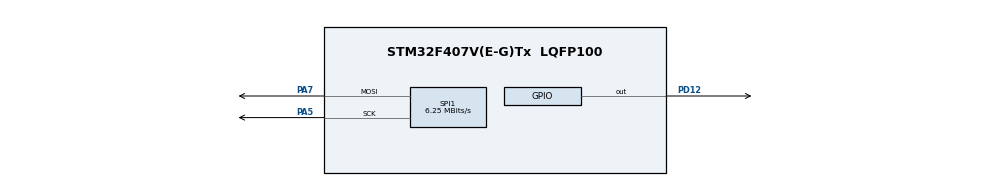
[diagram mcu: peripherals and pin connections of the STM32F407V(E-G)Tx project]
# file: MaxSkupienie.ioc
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Mcu.Family=STM32F4
Mcu.Name=STM32F407V(E-G)Tx
Mcu.Package=LQFP100
NVIC.PriorityGroup=NVIC_PRIORITYGROUP_4
PA13.Mode=Serial_Wire
PA13.Signal=SYS_JTMS-SWDIO
PA14.Mode=Serial_Wire
PA14.Signal=SYS_JTCK-SWCLK
PA5.Mode=TX_Only_Simplex_Unidirect_Master
PA5.Signal=SPI1_SCK
PA7.Mode=TX_Only_Simplex_Unidirect_Master
PA7.Signal=SPI1_MOSI
PC14-OSC32_IN.Mode=LSE-External-Oscillator
PC14-OSC32_IN.Signal=RCC_OSC32_IN
PC15-OSC32_OUT.Mode=LSE-External-Oscillator
PC15-OSC32_OUT.Signal=RCC_OSC32_OUT
PD12.Signal=GPIO_Output
PH0-OSC_IN.Mode=HSE-External-Oscillator
PH0-OSC_IN.Signal=RCC_OSC_IN
PH1-OSC_OUT.Mode=HSE-External-Oscillator
PH1-OSC_OUT.Signal=RCC_OSC_OUT
ProjectManager.HeapSize=0x200
ProjectManager.StackSize=0x400
ProjectManager.TargetToolchain=SW4STM32
RCC.48MHZClocksFreq_Value=50000000
RCC.AHBFreq_Value=100000000
RCC.APB1CLKDivider=RCC_HCLK_DIV4
RCC.APB1Freq_Value=25000000
RCC.APB1TimFreq_Value=50000000
RCC.APB2CLKDivider=RCC_HCLK_DIV2
RCC.APB2Freq_Value=50000000
RCC.APB2TimFreq_Value=100000000
RCC.CortexFreq_Value=100000000
RCC.HCLKFreq_Value=100000000
RCC.HSE_VALUE=8000000
RCC.HSI_VALUE=16000000
RCC.PLLM=4
RCC.PLLN=100
RCC.PLLSourceVirtual=RCC_PLLSOURCE_HSE
RCC.SYSCLKFreq_VALUE=100000000
RCC.SYSCLKSource=RCC_SYSCLKSOURCE_PLLCLK
RCC.VCOOutputFreq_Value=200000000
SPI1.BaudRatePrescaler=SPI_BAUDRATEPRESCALER_8
SPI1.CalculateBaudRate=6.25 MBits/s
SPI1.Direction=SPI_DIRECTION_2LINES
SPI1.Mode=SPI_MODE_MASTER
SPI1.VirtualType=VM_MASTER
board=custom

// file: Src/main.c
/**
  ******************************************************************************
  * @file           : main.c
  * @brief          : Main program body
  ******************************************************************************
  ** This notice applies to any and all portions of this file
  * that are not between comment pairs USER CODE BEGIN and
  * USER CODE END. Other portions of this file, whether
  * inserted by the user or by software development tools
  * are owned by their respective copyright owners.
  *
  * COPYRIGHT(c) 2019 STMicroelectronics
  *
  * Redistribution and use in source and binary forms, with or without modification,
  * are permitted provided that the following conditions are met:
  *   1. Redistributions of source code must retain the above copyright notice,
  *      this list of conditions and the following disclaimer.
  *   2. Redistributions in binary form must reproduce the above copyright notice,
  *      this list of conditions and the following disclaimer in the documentation
  *      and/or other materials provided with the distribution.
  *   3. Neither the name of STMicroelectronics nor the names of its contributors
  *      may be used to endorse or promote products derived from this software
  *      without specific prior written permission.
  *
  * THIS SOFTWARE IS PROVIDED BY THE COPYRIGHT HOLDERS AND CONTRIBUTORS "AS IS"
  * AND ANY EXPRESS OR IMPLIED WARRANTIES, INCLUDING, BUT NOT LIMITED TO, THE
  * IMPLIED WARRANTIES OF MERCHANTABILITY AND FITNESS FOR A PARTICULAR PURPOSE ARE
  * DISCLAIMED. IN NO EVENT SHALL THE COPYRIGHT HOLDER OR CONTRIBUTORS BE LIABLE
  * FOR ANY DIRECT, INDIRECT, INCIDENTAL, SPECIAL, EXEMPLARY, OR CONSEQUENTIAL
  * DAMAGES (INCLUDING, BUT NOT LIMITED TO, PROCUREMENT OF SUBSTITUTE GOODS OR
  * SERVICES; LOSS OF USE, DATA, OR PROFITS; OR BUSINESS INTERRUPTION) HOWEVER
  * CAUSED AND ON ANY THEORY OF LIABILITY, WHETHER IN CONTRACT, STRICT LIABILITY,
  * OR TORT (INCLUDING NEGLIGENCE OR OTHERWISE) ARISING IN ANY WAY OUT OF THE USE
  * OF THIS SOFTWARE, EVEN IF ADVISED OF THE POSSIBILITY OF SUCH DAMAGE.
  *
  ******************************************************************************
  */
#include "main.h"
#include "stm32f4xx_hal.h"
#include "ws2812b.h"
#include "light.h"

#define Led_Count 3

SPI_HandleTypeDef hspi1;
const uint8_t zero = 0b00011111;
const uint8_t one = 0b00000111;

/* USER CODE BEGIN PV */
/* Private variables ---------------------------------------------------------*/

/* USER CODE END PV */

void SystemClock_Config(void);
static void MX_GPIO_Init(void);
static void MX_SPI1_Init(void);

/* USER CODE BEGIN PFP */
/* Private function prototypes -----------------------------------------------*/

/* USER CODE END PFP */

int main(void)
{

  /* MCU Configuration----------------------------------------------------------*/

  /* Reset of all peripherals, Initializes the Flash interface and the Systick. */
  HAL_Init();

  /* Configure the system clock */
  SystemClock_Config();

  /* Initialize all configured peripherals */
  MX_GPIO_Init();
  MX_SPI1_Init();
  /* USER CODE BEGIN 2 */
  	ws2812b_config led_strip_c = ws2812b_init(&hspi1, Led_Count);
  	lighting_config l_c = lighting_init(Led_Count);
//HSV
  	lighting_hsv from_color, to_color;
  	from_color.hue = 200;
  	from_color.value = 0.5;

  	to_color.hue = 360;
  	to_color.value = 0.5;
//RGB
  	lighting_rgb new_color;
  	new_color.red = 30;
  	new_color.green = 57;
  	new_color.blue = 57;
  /* USER CODE END 2 */
  	/*
  		lighting_draw_gradient_rgb(&l_c, 0, Led_Count,new_color, new_color);
		lighting_update_ws2812b(&l_c, &led_strip_c);
		ws2812b_refresh(&led_strip_c);
		HAL_Delay(20);
  	 */

  /* Infinite loop */
  while (1)
  {

  /* USER CODE BEGIN 3 */
	 /*
	 for(int j = 0;j<3;j++)
	  {
		  lighting_set_diode_color_rgb(&l_c,j,new_color);
		  lighting_update_ws2812b(&l_c, &led_strip_c);
		  ws2812b_refresh(&led_strip_c);
		  HAL_Delay(20);
	  }
	  */

	  for (double i = 0; i < 2; i += 0.01)
	  {
			double j;
			if (i > 1)
				j = 2 - i;
			else
				j = i;

			from_color.saturation = j;
			to_color.saturation = j;

			lighting_draw_gradient_hsv(&l_c, 0, Led_Count, from_color, to_color);
			lighting_update_ws2812b(&l_c, &led_strip_c);
			ws2812b_refresh(&led_strip_c);
			HAL_Delay(20);
		}
		double tmp;
		tmp = from_color.hue;
		from_color.hue = to_color.hue;
		to_color.hue = tmp;

  }
  /* USER CODE END 3 */

}

void SystemClock_Config(void)
{

  RCC_OscInitTypeDef RCC_OscInitStruct;
  RCC_ClkInitTypeDef RCC_ClkInitStruct;

    /**Configure the main internal regulator output voltage
    */
  __HAL_RCC_PWR_CLK_ENABLE();

  __HAL_PWR_VOLTAGESCALING_CONFIG(PWR_REGULATOR_VOLTAGE_SCALE1);

    /**Initializes the CPU, AHB and APB busses clocks
    */
  RCC_OscInitStruct.OscillatorType = RCC_OSCILLATORTYPE_HSE;
  RCC_OscInitStruct.HSEState = RCC_HSE_ON;
  RCC_OscInitStruct.PLL.PLLState = RCC_PLL_ON;
  RCC_OscInitStruct.PLL.PLLSource = RCC_PLLSOURCE_HSE;
  RCC_OscInitStruct.PLL.PLLM = 4;
  RCC_OscInitStruct.PLL.PLLN = 103;
  RCC_OscInitStruct.PLL.PLLP = RCC_PLLP_DIV2;
  RCC_OscInitStruct.PLL.PLLQ = 4;
  if (HAL_RCC_OscConfig(&RCC_OscInitStruct) != HAL_OK)
  {
    _Error_Handler(__FILE__, __LINE__);
  }

    /**Initializes the CPU, AHB and APB busses clocks
    */
  RCC_ClkInitStruct.ClockType = RCC_CLOCKTYPE_HCLK|RCC_CLOCKTYPE_SYSCLK
                              |RCC_CLOCKTYPE_PCLK1|RCC_CLOCKTYPE_PCLK2;
  RCC_ClkInitStruct.SYSCLKSource = RCC_SYSCLKSOURCE_PLLCLK;
  RCC_ClkInitStruct.AHBCLKDivider = RCC_SYSCLK_DIV1;
  RCC_ClkInitStruct.APB1CLKDivider = RCC_HCLK_DIV4;
  RCC_ClkInitStruct.APB2CLKDivider = RCC_HCLK_DIV2;

  if (HAL_RCC_ClockConfig(&RCC_ClkInitStruct, FLASH_LATENCY_3) != HAL_OK)
  {
    _Error_Handler(__FILE__, __LINE__);
  }

    /**Configure the Systick interrupt time
    */
  HAL_SYSTICK_Config(HAL_RCC_GetHCLKFreq()/1000);

    /**Configure the Systick
    */
  HAL_SYSTICK_CLKSourceConfig(SYSTICK_CLKSOURCE_HCLK);

  /* SysTick_IRQn interrupt configuration */
  HAL_NVIC_SetPriority(SysTick_IRQn, 0, 0);
}

/* SPI1 init function */
static void MX_SPI1_Init(void)
{

  /* SPI1 parameter configuration*/
  hspi1.Instance = SPI1;
  hspi1.Init.Mode = SPI_MODE_MASTER;
  hspi1.Init.Direction = SPI_DIRECTION_2LINES;
  hspi1.Init.DataSize = SPI_DATASIZE_8BIT;
  hspi1.Init.CLKPolarity = SPI_POLARITY_LOW;
  hspi1.Init.CLKPhase = SPI_PHASE_1EDGE;
  hspi1.Init.NSS = SPI_NSS_SOFT;
  hspi1.Init.BaudRatePrescaler = SPI_BAUDRATEPRESCALER_8;
  hspi1.Init.FirstBit = SPI_FIRSTBIT_MSB;
  hspi1.Init.TIMode = SPI_TIMODE_DISABLE;
  hspi1.Init.CRCCalculation = SPI_CRCCALCULATION_DISABLE;
  hspi1.Init.CRCPolynomial = 10;
  if (HAL_SPI_Init(&hspi1) != HAL_OK)
  {
    _Error_Handler(__FILE__, __LINE__);
  }

}

/** Configure pins as
        * Analog
        * Input
        * Output
        * EVENT_OUT
        * EXTI
*/
static void MX_GPIO_Init(void)
{

  GPIO_InitTypeDef GPIO_InitStruct;

  /* GPIO Ports Clock Enable */
  __HAL_RCC_GPIOC_CLK_ENABLE();
  __HAL_RCC_GPIOH_CLK_ENABLE();
  __HAL_RCC_GPIOA_CLK_ENABLE();
  __HAL_RCC_GPIOD_CLK_ENABLE();

  /*Configure GPIO pin Output Level */
  HAL_GPIO_WritePin(GPIOD, GPIO_PIN_12, GPIO_PIN_RESET);

  /*Configure GPIO pin : PD12 */
  GPIO_InitStruct.Pin = GPIO_PIN_12;
  GPIO_InitStruct.Mode = GPIO_MODE_OUTPUT_PP;
  GPIO_InitStruct.Pull = GPIO_NOPULL;
  GPIO_InitStruct.Speed = GPIO_SPEED_FREQ_LOW;
  HAL_GPIO_Init(GPIOD, &GPIO_InitStruct);

}

void _Error_Handler(char *file, int line)
{
  while(1)
  {
  }
}

/************************ (C) COPYRIGHT STMicroelectronics *****END OF FILE****/
